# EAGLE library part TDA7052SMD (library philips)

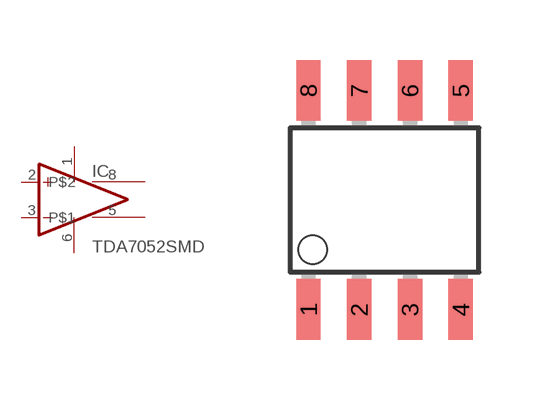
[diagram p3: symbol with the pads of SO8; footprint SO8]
Designator prefix IC

## TDA7052SMD  [SO8]
1  V+  pwr
2  +IN  in
3  -IN  in
5  P$1  out
6  V-  pwr
8  P$2  out

## Footprint SO8 (pad centres in mm)
smd 0.61 x 1.524: 1 -1.27,-2.743; 2 0,-2.743; 3 1.27,-2.743; 4 2.54,-2.743; 5 2.54,2.743; 6 1.27,2.743; 7 0,2.743; 8 -1.27,2.743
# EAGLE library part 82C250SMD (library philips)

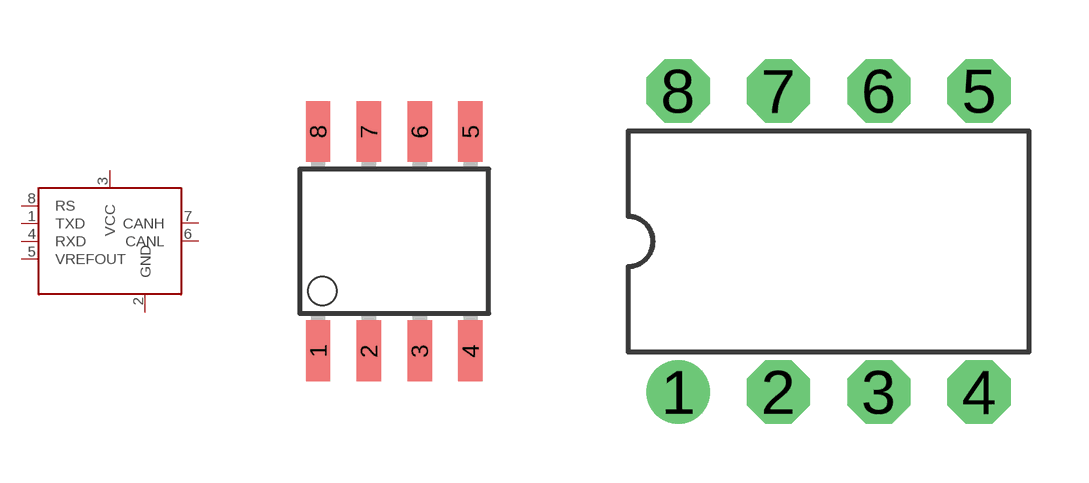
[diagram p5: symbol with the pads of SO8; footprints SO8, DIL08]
Designator prefix IC

## 82C250SMDSMD  [SO8]
1  TXD  in
2  GND  sup
3  VCC  sup
4  RXD  out
5  VREFOUT  out
6  CANL
7  CANH
8  RS  in

## 82C250SMDDIL  [DIL08]
Pads as for SO8

## Footprint SO8 (pad centres in mm)
smd 0.61 x 1.524: 1 -1.27,-2.743; 2 0,-2.743; 3 1.27,-2.743; 4 2.54,-2.743; 5 2.54,2.743; 6 1.27,2.743; 7 0,2.743; 8 -1.27,2.743

## Footprint DIL08 (pad centres in mm)
drill 0.813 pad 1.6 round: 1 -3.81,-3.81
drill 0.813 pad 1.6 octagon: 2 -1.27,-3.81; 3 1.27,-3.81; 4 3.81,-3.81; 5 3.81,3.81; 6 1.27,3.81; 7 -1.27,3.81; 8 -3.81,3.81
